# Generated deterministically by seda-macro-lef-normalizer-v1; recipe orfs-ng45-fakeram-metal3-coupledl2-pg-v1.
VERSION 5.8 ;
BUSBITCHARS "[]" ;
DIVIDERCHAR "/" ;

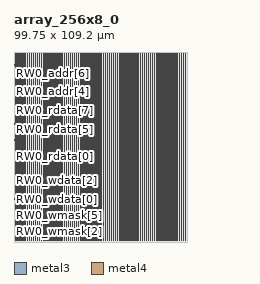
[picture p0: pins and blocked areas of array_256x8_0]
MACRO array_256x8_0
  FOREIGN array_256x8_0 0 0 ;
  CLASS BLOCK ;
  ORIGIN 0 0 ;
  SIZE 99.75 BY 109.2 ;
  SYMMETRY X Y R90 ;
  PIN RW0_wmask[0]
    DIRECTION INPUT ;
    USE SIGNAL ;
    SHAPE ABUTMENT ;
    PORT
      LAYER metal3 ;
      RECT 0 0.035 0.07 0.105 ;
    END
  END RW0_wmask[0]
  PIN RW0_wmask[1]
    DIRECTION INPUT ;
    USE SIGNAL ;
    SHAPE ABUTMENT ;
    PORT
      LAYER metal3 ;
      RECT 0 3.115 0.07 3.185 ;
    END
  END RW0_wmask[1]
  PIN RW0_wmask[2]
    DIRECTION INPUT ;
    USE SIGNAL ;
    SHAPE ABUTMENT ;
    PORT
      LAYER metal3 ;
      RECT 0 6.195 0.07 6.265 ;
    END
  END RW0_wmask[2]
  PIN RW0_wmask[3]
    DIRECTION INPUT ;
    USE SIGNAL ;
    SHAPE ABUTMENT ;
    PORT
      LAYER metal3 ;
      RECT 0 9.275 0.07 9.345 ;
    END
  END RW0_wmask[3]
  PIN RW0_wmask[4]
    DIRECTION INPUT ;
    USE SIGNAL ;
    SHAPE ABUTMENT ;
    PORT
      LAYER metal3 ;
      RECT 0 12.355 0.07 12.425 ;
    END
  END RW0_wmask[4]
  PIN RW0_wmask[5]
    DIRECTION INPUT ;
    USE SIGNAL ;
    SHAPE ABUTMENT ;
    PORT
      LAYER metal3 ;
      RECT 0 15.435 0.07 15.505 ;
    END
  END RW0_wmask[5]
  PIN RW0_wmask[6]
    DIRECTION INPUT ;
    USE SIGNAL ;
    SHAPE ABUTMENT ;
    PORT
      LAYER metal3 ;
      RECT 0 18.515 0.07 18.585 ;
    END
  END RW0_wmask[6]
  PIN RW0_wmask[7]
    DIRECTION INPUT ;
    USE SIGNAL ;
    SHAPE ABUTMENT ;
    PORT
      LAYER metal3 ;
      RECT 0 21.595 0.07 21.665 ;
    END
  END RW0_wmask[7]
  PIN RW0_wdata[0]
    DIRECTION INPUT ;
    USE SIGNAL ;
    SHAPE ABUTMENT ;
    PORT
      LAYER metal3 ;
      RECT 0 24.675 0.07 24.745 ;
    END
  END RW0_wdata[0]
  PIN RW0_wdata[1]
    DIRECTION INPUT ;
    USE SIGNAL ;
    SHAPE ABUTMENT ;
    PORT
      LAYER metal3 ;
      RECT 0 27.755 0.07 27.825 ;
    END
  END RW0_wdata[1]
  PIN RW0_wdata[2]
    DIRECTION INPUT ;
    USE SIGNAL ;
    SHAPE ABUTMENT ;
    PORT
      LAYER metal3 ;
      RECT 0 30.835 0.07 30.905 ;
    END
  END RW0_wdata[2]
  PIN RW0_wdata[3]
    DIRECTION INPUT ;
    USE SIGNAL ;
    SHAPE ABUTMENT ;
    PORT
      LAYER metal3 ;
      RECT 0 33.915 0.07 33.985 ;
    END
  END RW0_wdata[3]
  PIN RW0_wdata[4]
    DIRECTION INPUT ;
    USE SIGNAL ;
    SHAPE ABUTMENT ;
    PORT
      LAYER metal3 ;
      RECT 0 36.995 0.07 37.065 ;
    END
  END RW0_wdata[4]
  PIN RW0_wdata[5]
    DIRECTION INPUT ;
    USE SIGNAL ;
    SHAPE ABUTMENT ;
    PORT
      LAYER metal3 ;
      RECT 0 40.075 0.07 40.145 ;
    END
  END RW0_wdata[5]
  PIN RW0_wdata[6]
    DIRECTION INPUT ;
    USE SIGNAL ;
    SHAPE ABUTMENT ;
    PORT
      LAYER metal3 ;
      RECT 0 43.155 0.07 43.225 ;
    END
  END RW0_wdata[6]
  PIN RW0_wdata[7]
    DIRECTION INPUT ;
    USE SIGNAL ;
    SHAPE ABUTMENT ;
    PORT
      LAYER metal3 ;
      RECT 0 46.235 0.07 46.305 ;
    END
  END RW0_wdata[7]
  PIN RW0_rdata[0]
    DIRECTION OUTPUT ;
    USE SIGNAL ;
    SHAPE ABUTMENT ;
    PORT
      LAYER metal3 ;
      RECT 0 49.315 0.07 49.385 ;
    END
  END RW0_rdata[0]
  PIN RW0_rdata[1]
    DIRECTION OUTPUT ;
    USE SIGNAL ;
    SHAPE ABUTMENT ;
    PORT
      LAYER metal3 ;
      RECT 0 52.395 0.07 52.465 ;
    END
  END RW0_rdata[1]
  PIN RW0_rdata[2]
    DIRECTION OUTPUT ;
    USE SIGNAL ;
    SHAPE ABUTMENT ;
    PORT
      LAYER metal3 ;
      RECT 0 55.475 0.07 55.545 ;
    END
  END RW0_rdata[2]
  PIN RW0_rdata[3]
    DIRECTION OUTPUT ;
    USE SIGNAL ;
    SHAPE ABUTMENT ;
    PORT
      LAYER metal3 ;
      RECT 0 58.555 0.07 58.625 ;
    END
  END RW0_rdata[3]
  PIN RW0_rdata[4]
    DIRECTION OUTPUT ;
    USE SIGNAL ;
    SHAPE ABUTMENT ;
    PORT
      LAYER metal3 ;
      RECT 0 61.635 0.07 61.705 ;
    END
  END RW0_rdata[4]
  PIN RW0_rdata[5]
    DIRECTION OUTPUT ;
    USE SIGNAL ;
    SHAPE ABUTMENT ;
    PORT
      LAYER metal3 ;
      RECT 0 64.715 0.07 64.785 ;
    END
  END RW0_rdata[5]
  PIN RW0_rdata[6]
    DIRECTION OUTPUT ;
    USE SIGNAL ;
    SHAPE ABUTMENT ;
    PORT
      LAYER metal3 ;
      RECT 0 67.795 0.07 67.865 ;
    END
  END RW0_rdata[6]
  PIN RW0_rdata[7]
    DIRECTION OUTPUT ;
    USE SIGNAL ;
    SHAPE ABUTMENT ;
    PORT
      LAYER metal3 ;
      RECT 0 70.875 0.07 70.945 ;
    END
  END RW0_rdata[7]
  PIN RW0_addr[0]
    DIRECTION INPUT ;
    USE SIGNAL ;
    SHAPE ABUTMENT ;
    PORT
      LAYER metal3 ;
      RECT 0 73.955 0.07 74.025 ;
    END
  END RW0_addr[0]
  PIN RW0_addr[1]
    DIRECTION INPUT ;
    USE SIGNAL ;
    SHAPE ABUTMENT ;
    PORT
      LAYER metal3 ;
      RECT 0 77.035 0.07 77.105 ;
    END
  END RW0_addr[1]
  PIN RW0_addr[2]
    DIRECTION INPUT ;
    USE SIGNAL ;
    SHAPE ABUTMENT ;
    PORT
      LAYER metal3 ;
      RECT 0 80.115 0.07 80.185 ;
    END
  END RW0_addr[2]
  PIN RW0_addr[3]
    DIRECTION INPUT ;
    USE SIGNAL ;
    SHAPE ABUTMENT ;
    PORT
      LAYER metal3 ;
      RECT 0 83.195 0.07 83.265 ;
    END
  END RW0_addr[3]
  PIN RW0_addr[4]
    DIRECTION INPUT ;
    USE SIGNAL ;
    SHAPE ABUTMENT ;
    PORT
      LAYER metal3 ;
      RECT 0 86.275 0.07 86.345 ;
    END
  END RW0_addr[4]
  PIN RW0_addr[5]
    DIRECTION INPUT ;
    USE SIGNAL ;
    SHAPE ABUTMENT ;
    PORT
      LAYER metal3 ;
      RECT 0 89.355 0.07 89.425 ;
    END
  END RW0_addr[5]
  PIN RW0_addr[6]
    DIRECTION INPUT ;
    USE SIGNAL ;
    SHAPE ABUTMENT ;
    PORT
      LAYER metal3 ;
      RECT 0 92.435 0.07 92.505 ;
    END
  END RW0_addr[6]
  PIN RW0_addr[7]
    DIRECTION INPUT ;
    USE SIGNAL ;
    SHAPE ABUTMENT ;
    PORT
      LAYER metal3 ;
      RECT 0 95.515 0.07 95.585 ;
    END
  END RW0_addr[7]
  PIN RW0_wmode
    DIRECTION INPUT ;
    USE SIGNAL ;
    SHAPE ABUTMENT ;
    PORT
      LAYER metal3 ;
      RECT 0 98.595 0.07 98.665 ;
    END
  END RW0_wmode
  PIN RW0_en
    DIRECTION INPUT ;
    USE SIGNAL ;
    SHAPE ABUTMENT ;
    PORT
      LAYER metal3 ;
      RECT 0 101.675 0.07 101.745 ;
    END
  END RW0_en
  PIN RW0_clk
    DIRECTION INPUT ;
    USE SIGNAL ;
    SHAPE ABUTMENT ;
    PORT
      LAYER metal3 ;
      RECT 0 104.755 0.07 104.825 ;
    END
  END RW0_clk
  PIN VSS
    DIRECTION INOUT ;
    USE GROUND ;
    PORT
      LAYER metal4 ;
      RECT 1 0.84 1.28 108.36 ;
      RECT 3.24 0.84 3.52 108.36 ;
      RECT 5.48 0.84 5.76 108.36 ;
      RECT 7.72 0.84 8 108.36 ;
      RECT 9.96 0.84 10.24 108.36 ;
      RECT 12.2 0.84 12.48 108.36 ;
      RECT 14.44 0.84 14.72 108.36 ;
      RECT 16.68 0.84 16.96 108.36 ;
      RECT 18.92 0.84 19.2 108.36 ;
      RECT 21.16 0.84 21.44 108.36 ;
      RECT 23.4 0.84 23.68 108.36 ;
      RECT 25.64 0.84 25.92 108.36 ;
      RECT 27.88 0.84 28.16 108.36 ;
      RECT 30.12 0.84 30.4 108.36 ;
      RECT 32.36 0.84 32.64 108.36 ;
      RECT 34.6 0.84 34.88 108.36 ;
      RECT 36.84 0.84 37.12 108.36 ;
      RECT 39.08 0.84 39.36 108.36 ;
      RECT 41.32 0.84 41.6 108.36 ;
      RECT 43.56 0.84 43.84 108.36 ;
      RECT 45.8 0.84 46.08 108.36 ;
      RECT 48.04 0.84 48.32 108.36 ;
      RECT 50.28 0.84 50.56 108.36 ;
      RECT 52.52 0.84 52.8 108.36 ;
      RECT 54.76 0.84 55.04 108.36 ;
      RECT 57 0.84 57.28 108.36 ;
      RECT 59.24 0.84 59.52 108.36 ;
      RECT 61.48 0.84 61.76 108.36 ;
      RECT 63.72 0.84 64 108.36 ;
      RECT 65.96 0.84 66.24 108.36 ;
      RECT 68.2 0.84 68.48 108.36 ;
      RECT 70.44 0.84 70.72 108.36 ;
      RECT 72.68 0.84 72.96 108.36 ;
      RECT 74.92 0.84 75.2 108.36 ;
      RECT 77.16 0.84 77.44 108.36 ;
      RECT 79.4 0.84 79.68 108.36 ;
      RECT 81.64 0.84 81.92 108.36 ;
      RECT 83.88 0.84 84.16 108.36 ;
      RECT 86.12 0.84 86.4 108.36 ;
      RECT 88.36 0.84 88.64 108.36 ;
      RECT 90.6 0.84 90.88 108.36 ;
      RECT 92.84 0.84 93.12 108.36 ;
      RECT 95.08 0.84 95.36 108.36 ;
      RECT 97.32 0.84 97.6 108.36 ;
    END
  END VSS
  PIN VDD
    DIRECTION INOUT ;
    USE POWER ;
    PORT
      LAYER metal4 ;
      RECT 2.12 0.84 2.4 108.36 ;
      RECT 4.36 0.84 4.64 108.36 ;
      RECT 6.6 0.84 6.88 108.36 ;
      RECT 8.84 0.84 9.12 108.36 ;
      RECT 11.08 0.84 11.36 108.36 ;
      RECT 13.32 0.84 13.6 108.36 ;
      RECT 15.56 0.84 15.84 108.36 ;
      RECT 17.8 0.84 18.08 108.36 ;
      RECT 20.04 0.84 20.32 108.36 ;
      RECT 22.28 0.84 22.56 108.36 ;
      RECT 24.52 0.84 24.8 108.36 ;
      RECT 26.76 0.84 27.04 108.36 ;
      RECT 29 0.84 29.28 108.36 ;
      RECT 31.24 0.84 31.52 108.36 ;
      RECT 33.48 0.84 33.76 108.36 ;
      RECT 35.72 0.84 36 108.36 ;
      RECT 37.96 0.84 38.24 108.36 ;
      RECT 40.2 0.84 40.48 108.36 ;
      RECT 42.44 0.84 42.72 108.36 ;
      RECT 44.68 0.84 44.96 108.36 ;
      RECT 46.92 0.84 47.2 108.36 ;
      RECT 49.16 0.84 49.44 108.36 ;
      RECT 51.4 0.84 51.68 108.36 ;
      RECT 53.64 0.84 53.92 108.36 ;
      RECT 55.88 0.84 56.16 108.36 ;
      RECT 58.12 0.84 58.4 108.36 ;
      RECT 60.36 0.84 60.64 108.36 ;
      RECT 62.6 0.84 62.88 108.36 ;
      RECT 64.84 0.84 65.12 108.36 ;
      RECT 67.08 0.84 67.36 108.36 ;
      RECT 69.32 0.84 69.6 108.36 ;
      RECT 71.56 0.84 71.84 108.36 ;
      RECT 73.8 0.84 74.08 108.36 ;
      RECT 76.04 0.84 76.32 108.36 ;
      RECT 78.28 0.84 78.56 108.36 ;
      RECT 80.52 0.84 80.8 108.36 ;
      RECT 82.76 0.84 83.04 108.36 ;
      RECT 85 0.84 85.28 108.36 ;
      RECT 87.24 0.84 87.52 108.36 ;
      RECT 89.48 0.84 89.76 108.36 ;
      RECT 91.72 0.84 92 108.36 ;
      RECT 93.96 0.84 94.24 108.36 ;
      RECT 96.2 0.84 96.48 108.36 ;
      RECT 98.44 0.84 98.72 108.36 ;
    END
  END VDD
  OBS
    LAYER metal1 ;
    RECT 0 0 99.75 109.2 ;
    LAYER metal2 ;
    RECT 0 0 99.75 109.2 ;
  END
END array_256x8_0

END LIBRARY
